VERSION 5.7 ;
  NOWIREEXTENSIONATPIN ON ;
  DIVIDERCHAR "/" ;
  BUSBITCHARS "[]" ;
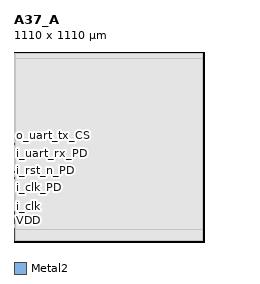
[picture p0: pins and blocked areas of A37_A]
MACRO A37_A
  CLASS BLOCK ;
  FOREIGN A37_A ;
  ORIGIN 0.000 0.000 ;
  SIZE 1110.000 BY 1110.000 ;
  PIN VDD
    DIRECTION INPUT ;
    USE POWER ;
    PORT
      LAYER Metal2 ;
        RECT 0.000 106.360 2.000 119.340 ;
    END
  END VDD
  PIN VDD
    DIRECTION INPUT ;
    USE POWER ;
    PORT
      LAYER Metal2 ;
        RECT 0.000 118.760 1.000 129.010 ;
    END
  END VDD
  PIN VDD
    DIRECTION INPUT ;
    USE POWER ;
    PORT
      LAYER Metal2 ;
        RECT 0.000 129.010 2.000 178.640 ;
    END
  END VDD
  PIN VDD
    DIRECTION INPUT ;
    USE POWER ;
    PORT
      LAYER Metal2 ;
        RECT 0.000 144.140 1.000 154.390 ;
    END
  END VDD
  PIN VDD
    DIRECTION INPUT ;
    USE POWER ;
    PORT
      LAYER Metal2 ;
        RECT 0.000 155.990 1.000 166.240 ;
    END
  END VDD
  PIN VDD
    DIRECTION INPUT ;
    USE POWER ;
    PORT
      LAYER Metal2 ;
        RECT 0.000 169.140 1.000 178.640 ;
    END
  END VDD
  PIN VSS
    DIRECTION INPUT ;
    USE GROUND ;
    PORT
      LAYER Metal2 ;
        RECT 0.000 6.360 2.000 64.340 ;
    END
  END VSS
  PIN VSS
    DIRECTION INPUT ;
    USE GROUND ;
    PORT
      LAYER Metal2 ;
        RECT 0.000 18.760 1.000 29.010 ;
    END
  END VSS
  PIN VSS
    DIRECTION INPUT ;
    USE GROUND ;
    PORT
      LAYER Metal2 ;
        RECT 0.000 30.610 1.000 40.860 ;
    END
  END VSS
  PIN VSS
    DIRECTION INPUT ;
    USE GROUND ;
    PORT
      LAYER Metal2 ;
        RECT 0.000 44.140 1.000 54.390 ;
    END
  END VSS
  PIN VSS
    DIRECTION INPUT ;
    USE GROUND ;
    PORT
      LAYER Metal2 ;
        RECT 0.000 55.990 1.000 66.240 ;
    END
  END VSS
  PIN VSS
    DIRECTION INPUT ;
    USE GROUND ;
    PORT
      LAYER Metal2 ;
        RECT 0.000 66.240 2.000 78.640 ;
    END
  END VSS
  PIN i_clk
    DIRECTION INPUT ;
    USE SIGNAL ;
    ANTENNAGATEAREA 4.738000 ;
    PORT
      LAYER Metal2 ;
        RECT 0.000 208.760 1.000 209.140 ;
    END
  END i_clk
  PIN i_clk_PD
    DIRECTION OUTPUT ;
    USE SIGNAL ;
    ANTENNADIFFAREA 0.360800 ;
    PORT
      LAYER Metal2 ;
        RECT 0.000 269.290 1.000 269.670 ;
    END
  END i_clk_PD
  PIN i_clk_PU
    DIRECTION OUTPUT ;
    USE SIGNAL ;
    ANTENNADIFFAREA 0.360800 ;
    PORT
      LAYER Metal2 ;
        RECT 0.000 273.655 1.000 274.035 ;
    END
  END i_clk_PU
  PIN i_rst_n
    DIRECTION INPUT ;
    USE SIGNAL ;
    ANTENNAGATEAREA 11.020000 ;
    PORT
      LAYER Metal2 ;
        RECT 0.000 308.760 1.000 309.140 ;
    END
  END i_rst_n
  PIN i_rst_n_PD
    DIRECTION OUTPUT ;
    USE SIGNAL ;
    ANTENNADIFFAREA 0.360800 ;
    PORT
      LAYER Metal2 ;
        RECT 0.000 369.290 1.000 369.670 ;
    END
  END i_rst_n_PD
  PIN i_rst_n_PU
    DIRECTION OUTPUT ;
    USE SIGNAL ;
    ANTENNADIFFAREA 0.536800 ;
    PORT
      LAYER Metal2 ;
        RECT 0.000 373.655 1.000 374.035 ;
    END
  END i_rst_n_PU
  PIN i_uart_rx
    DIRECTION INPUT ;
    USE SIGNAL ;
    ANTENNAGATEAREA 0.396000 ;
    PORT
      LAYER Metal2 ;
        RECT 0.000 408.760 1.000 409.140 ;
    END
  END i_uart_rx
  PIN i_uart_rx_PD
    DIRECTION OUTPUT ;
    USE SIGNAL ;
    ANTENNADIFFAREA 0.360800 ;
    PORT
      LAYER Metal2 ;
        RECT 0.000 469.290 1.000 469.670 ;
    END
  END i_uart_rx_PD
  PIN i_uart_rx_PU
    DIRECTION OUTPUT ;
    USE SIGNAL ;
    ANTENNADIFFAREA 0.360800 ;
    PORT
      LAYER Metal2 ;
        RECT 0.000 473.655 1.000 474.035 ;
    END
  END i_uart_rx_PU
  PIN o_uart_tx_CS
    DIRECTION OUTPUT ;
    USE SIGNAL ;
    ANTENNADIFFAREA 0.897600 ;
    PORT
      LAYER Metal2 ;
        RECT 0.000 576.260 1.000 576.640 ;
    END
  END o_uart_tx_CS
  PIN o_uart_tx_IE
    DIRECTION OUTPUT ;
    USE SIGNAL ;
    ANTENNADIFFAREA 0.360800 ;
    PORT
      LAYER Metal2 ;
        RECT 0.000 568.235 1.000 568.615 ;
    END
  END o_uart_tx_IE
  PIN o_uart_tx_IN
    DIRECTION INPUT ;
    USE SIGNAL ;
    ANTENNAGATEAREA 0.396000 ;
    PORT
      LAYER Metal2 ;
        RECT 0.000 508.760 1.000 509.140 ;
    END
  END o_uart_tx_IN
  PIN o_uart_tx_OE
    DIRECTION OUTPUT ;
    USE SIGNAL ;
    ANTENNADIFFAREA 0.536800 ;
    PORT
      LAYER Metal2 ;
        RECT 0.000 509.490 1.000 509.870 ;
    END
  END o_uart_tx_OE
  PIN o_uart_tx_OUT
    DIRECTION OUTPUT ;
    USE SIGNAL ;
    ANTENNADIFFAREA 0.897600 ;
    PORT
      LAYER Metal2 ;
        RECT 0.000 510.220 1.000 510.600 ;
    END
  END o_uart_tx_OUT
  PIN o_uart_tx_PD
    DIRECTION OUTPUT ;
    USE SIGNAL ;
    ANTENNADIFFAREA 0.360800 ;
    PORT
      LAYER Metal2 ;
        RECT 0.000 569.290 1.000 569.670 ;
    END
  END o_uart_tx_PD
  PIN o_uart_tx_PDRV0
    DIRECTION OUTPUT ;
    USE SIGNAL ;
    ANTENNADIFFAREA 0.536800 ;
    PORT
      LAYER Metal2 ;
        RECT 0.000 572.510 1.000 572.890 ;
    END
  END o_uart_tx_PDRV0
  PIN o_uart_tx_PDRV1
    DIRECTION OUTPUT ;
    USE SIGNAL ;
    ANTENNADIFFAREA 0.360800 ;
    PORT
      LAYER Metal2 ;
        RECT 0.000 571.800 1.000 572.180 ;
    END
  END o_uart_tx_PDRV1
  PIN o_uart_tx_PU
    DIRECTION OUTPUT ;
    USE SIGNAL ;
    ANTENNADIFFAREA 0.360800 ;
    PORT
      LAYER Metal2 ;
        RECT 0.000 573.655 1.000 574.035 ;
    END
  END o_uart_tx_PU
  PIN o_uart_tx_SL
    DIRECTION OUTPUT ;
    USE SIGNAL ;
    ANTENNADIFFAREA 0.360800 ;
    PORT
      LAYER Metal2 ;
        RECT 0.000 510.950 1.000 511.330 ;
    END
  END o_uart_tx_SL
  OBS
      LAYER Nwell ;
        RECT 29.810 30.930 1080.110 1078.430 ;
      LAYER Metal1 ;
        RECT 30.240 31.060 1079.680 1078.300 ;
      LAYER Metal2 ;
        RECT 0.140 576.940 1101.480 1099.800 ;
        RECT 1.300 575.960 1101.480 576.940 ;
        RECT 0.140 574.335 1101.480 575.960 ;
        RECT 1.300 573.355 1101.480 574.335 ;
        RECT 0.140 573.190 1101.480 573.355 ;
        RECT 1.300 571.500 1101.480 573.190 ;
        RECT 0.140 569.970 1101.480 571.500 ;
        RECT 1.300 568.990 1101.480 569.970 ;
        RECT 0.140 568.915 1101.480 568.990 ;
        RECT 1.300 567.935 1101.480 568.915 ;
        RECT 0.140 511.630 1101.480 567.935 ;
        RECT 1.300 508.460 1101.480 511.630 ;
        RECT 0.140 474.335 1101.480 508.460 ;
        RECT 1.300 473.355 1101.480 474.335 ;
        RECT 0.140 469.970 1101.480 473.355 ;
        RECT 1.300 468.990 1101.480 469.970 ;
        RECT 0.140 409.440 1101.480 468.990 ;
        RECT 1.300 408.460 1101.480 409.440 ;
        RECT 0.140 374.335 1101.480 408.460 ;
        RECT 1.300 373.355 1101.480 374.335 ;
        RECT 0.140 369.970 1101.480 373.355 ;
        RECT 1.300 368.990 1101.480 369.970 ;
        RECT 0.140 309.440 1101.480 368.990 ;
        RECT 1.300 308.460 1101.480 309.440 ;
        RECT 0.140 274.335 1101.480 308.460 ;
        RECT 1.300 273.355 1101.480 274.335 ;
        RECT 0.140 269.970 1101.480 273.355 ;
        RECT 1.300 268.990 1101.480 269.970 ;
        RECT 0.140 209.440 1101.480 268.990 ;
        RECT 1.300 208.460 1101.480 209.440 ;
        RECT 0.140 178.940 1101.480 208.460 ;
        RECT 2.300 128.710 1101.480 178.940 ;
        RECT 1.300 119.640 1101.480 128.710 ;
        RECT 2.300 106.060 1101.480 119.640 ;
        RECT 0.140 78.940 1101.480 106.060 ;
        RECT 2.300 65.940 1101.480 78.940 ;
        RECT 1.300 64.640 1101.480 65.940 ;
        RECT 2.300 9.560 1101.480 64.640 ;
      LAYER Metal3 ;
        RECT 0.090 9.560 1101.480 1099.800 ;
      LAYER Metal4 ;
        RECT 8.710 9.560 1101.210 1099.800 ;
      LAYER Metal5 ;
        RECT 8.440 70.680 1101.480 1071.670 ;
  END
END A37_A
END LIBRARY

